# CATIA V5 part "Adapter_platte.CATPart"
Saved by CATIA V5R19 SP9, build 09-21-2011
Part number: Adapter_platte
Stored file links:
  C:\Users\cpo_lkowalczyk\Desktop\CAD\Adapter_platte.CATPart

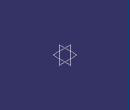
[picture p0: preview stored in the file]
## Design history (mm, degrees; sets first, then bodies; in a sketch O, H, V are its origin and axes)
Body1 (main body)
